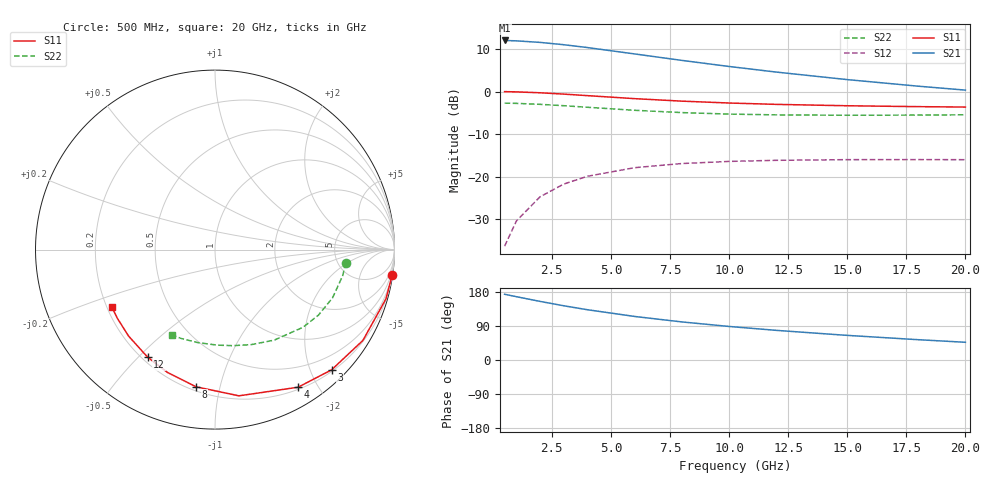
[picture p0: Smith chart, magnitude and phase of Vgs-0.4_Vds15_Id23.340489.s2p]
# Hz S RI R 50
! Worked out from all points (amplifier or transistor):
!   12 points, 500 MHz to 20 GHz, reference 50 ohm
!   highest |S21| = 12.0 dB at 500 MHz (marker M1)
!   |S21| within 3 dB of that: start of sweep to 5.788 GHz
!   unconditionally stable (mu >= 1): 18.45 GHz to end of sweep
!   at 2 GHz: K = 0.10, MSG = 18.1 dB, |S12| = -24.7 dB
!   at 8 GHz: K = 0.41, MSG = 12.1 dB, |S12| = -16.9 dB
!   at 20 GHz: K = 1.10, MAG = 6.2 dB, |S12| = -16.0 dB
!   S11 on the Smith chart (normalised r, x): 500 MHz: 0, -14; 3 GHz: 0.23, -2.34; 4 GHz: 0.23, -1.75; 8 GHz: 0.22, -0.85; 12 GHz: 0.22, -0.53; 20 GHz: 0.22, -0.25
5e8  0.9878 -0.1404  -3.949 0.4503  0.00148 0.0153  0.7279 -0.0731
1e9  0.9523 -0.2748  -3.832 0.8805  0.00579 0.0298  0.7122 -0.1436
2e9  0.824 -0.506  -3.409 1.615  0.0213 0.0542  0.655 -0.2688
3e9  0.6495 -0.67  -2.835 2.126  0.0423 0.0703  0.5762 -0.3653
4e9  0.4628 -0.7667  -2.225 2.413  0.0645 0.0782  0.4901 -0.4331
6e9  0.1334 -0.8147  -1.164 2.506  0.1028 0.0761  0.3299 -0.5045
8e9  -0.1046 -0.7646  -0.4226 2.281  0.1286 0.0626  0.2006 -0.5296
1e10  -0.2658 -0.6838  0.0513 1.967  0.1443 0.0461  0.0977 -0.5352
1.2e10  -0.3754 -0.5992  0.3457 1.656  0.1532 0.03  0.0123 -0.5322
1.5e10  -0.4809 -0.4825  0.5843 1.251  0.1586 0.00895  -0.0954 -0.5183
1.8e10  -0.5449 -0.3815  0.6863 0.9303  0.159 -0.00823  -0.1868 -0.4955
2e10  -0.5734 -0.3217  0.712 0.7573  0.1577 -0.0178  -0.2407 -0.4759
